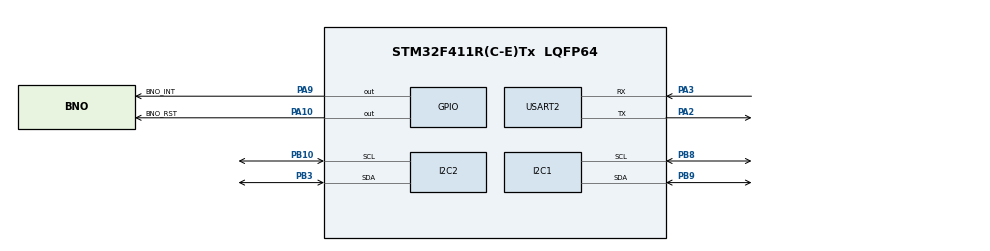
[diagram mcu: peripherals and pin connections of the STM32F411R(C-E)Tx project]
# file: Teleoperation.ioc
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I2C1.I2C_Mode=I2C_Fast
I2C2.I2C_Mode=I2C_Fast
Mcu.Family=STM32F4
Mcu.Name=STM32F411R(C-E)Tx
Mcu.Package=LQFP64
NVIC.PriorityGroup=NVIC_PRIORITYGROUP_4
PA10.GPIO_Label=BNO_RST
PA10.Signal=GPIO_Output
PA2.Mode=Asynchronous
PA2.Signal=USART2_TX
PA3.Mode=Asynchronous
PA3.Signal=USART2_RX
PA9.GPIO_Label=BNO_INT
PA9.Signal=GPIO_Output
PB10.Mode=I2C
PB10.Signal=I2C2_SCL
PB3.Mode=I2C
PB3.Signal=I2C2_SDA
PB8.Mode=I2C
PB8.Signal=I2C1_SCL
PB9.Mode=I2C
PB9.Signal=I2C1_SDA
ProjectManager.HeapSize=0x200
ProjectManager.StackSize=0x400
ProjectManager.TargetToolchain=STM32CubeIDE
RCC.AHBFreq_Value=16000000
RCC.APB1Freq_Value=16000000
RCC.APB2Freq_Value=16000000
RCC.CortexFreq_Value=16000000
RCC.HSE_VALUE=25000000
RCC.HSI_VALUE=16000000
RCC.LSE_VALUE=32768
RCC.SYSCLKFreq_VALUE=16000000
RCC.VCOOutputFreq_Value=192000000
USART2.VirtualMode=VM_ASYNC
VP_TIM2_VS_ClockSourceINT.Mode=Internal
board=custom

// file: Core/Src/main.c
/* USER CODE BEGIN Header */
/**
  ******************************************************************************
  * @file           : main.c
  * @brief          : Main program body
  ******************************************************************************
  * @attention
  *
  * Copyright (c) 2026 STMicroelectronics.
  * All rights reserved.
  *
  * This software is licensed under terms that can be found in the LICENSE file
  * in the root directory of this software component.
  * If no LICENSE file comes with this software, it is provided AS-IS.
  *
  ******************************************************************************
  */
/* USER CODE END Header */
#include "main.h"

/* USER CODE BEGIN Includes */
#include <stdio.h>
#include <stdint.h>
#include <string.h>
#include "BNO_08x_I2C.h"
/* USER CODE END Includes */

/* USER CODE BEGIN PD */
#define LSM_MAG_ADDR  (0x1E << 1)
/* USER CODE END PD */

I2C_HandleTypeDef hi2c1;
I2C_HandleTypeDef hi2c2;

TIM_HandleTypeDef htim2;

UART_HandleTypeDef huart2;

/* USER CODE BEGIN PV */
volatile uint8_t BNO_Ready = 0;
/* USER CODE END PV */

void SystemClock_Config(void);
static void MX_GPIO_Init(void);
static void MX_I2C1_Init(void);
static void MX_TIM2_Init(void);
static void MX_USART2_UART_Init(void);
static void MX_I2C2_Init(void);

/* USER CODE BEGIN 0 */
int16_t bx = 0, by = 0, bz = 0;   // фон
uint8_t mag_calibrated = 0;

int mag_read_raw(int16_t *mx, int16_t *my, int16_t *mz)
{
    uint8_t buf[6];
    uint8_t status;

    if (HAL_I2C_Mem_Read(&hi2c2, LSM_MAG_ADDR, 0x09, I2C_MEMADD_SIZE_8BIT, &status, 1, 100) != HAL_OK)
        return 0;

    if (!(status & 0x01))
        return 0;

    if (HAL_I2C_Mem_Read(&hi2c2, LSM_MAG_ADDR, 0x03, I2C_MEMADD_SIZE_8BIT, buf, 6, 100) != HAL_OK)
        return 0;

    *mx = (int16_t)((buf[0] << 8) | buf[1]);
    *mz = (int16_t)((buf[2] << 8) | buf[3]);
    *my = (int16_t)((buf[4] << 8) | buf[5]);

    return 1;
}

/* USER CODE END 0 */

int main(void)
{

  /* MCU Configuration--------------------------------------------------------*/

  /* Reset of all peripherals, Initializes the Flash interface and the Systick. */
  HAL_Init();

  /* Configure the system clock */
  SystemClock_Config();

  /* Initialize all configured peripherals */
  MX_GPIO_Init();
  MX_I2C1_Init();
  MX_TIM2_Init();
  MX_USART2_UART_Init();
  MX_I2C2_Init();
  /* USER CODE BEGIN 2 */

  #define MAG_AVERAGE_1  0x00  // 00
  #define MAG_AVERAGE_2  0x01  // 01
  #define MAG_AVERAGE_4  0x02  // 10
  #define MAG_AVERAGE_8  0x03  // 11

  #define MAG_RATE_0_75  0x00  // 000
  #define MAG_RATE_1_5   0x01  // 001
  #define MAG_RATE_3     0x02  // 010
  #define MAG_RATE_7_5   0x03  // 011
  #define MAG_RATE_15    0x04  // 100
  #define MAG_RATE_30    0x05  // 101
  #define MAG_RATE_75    0x06  // 110
  #define MAG_RATE_200    0x07  // 110

  uint8_t averaging = MAG_AVERAGE_1;
  uint8_t rate = MAG_RATE_75;
  uint8_t mode = 0x00; // 0x00 - нормальный режим

  uint8_t d = (averaging << 5) | (rate << 2) | mode;

  // CRA_REG_M
  HAL_I2C_Mem_Write(&hi2c2, LSM_MAG_ADDR, 0x00, 1, &d, 1, 1000);

  d = 0xE0;
  HAL_I2C_Mem_Write(&hi2c2, LSM_MAG_ADDR, 0x01, 1, &d, 1, 1000);

	// MR_REG_M (0x02): continuous-conversion
  d = 0x00;
  HAL_I2C_Mem_Write(&hi2c2, LSM_MAG_ADDR, 0x02, 1, &d, 1, 1000);

  HAL_TIM_Base_Start(&htim2);
  printf("Start!\r\n");
  printf("INT pin state: %d\r\n",
      HAL_GPIO_ReadPin(BNO_INT_GPIO_Port, BNO_INT_Pin));
  HAL_Delay(100);

  // Вручную сбрасываем сенсор
  HAL_GPIO_WritePin(BNO_RST_GPIO_Port, BNO_RST_Pin, GPIO_PIN_RESET); // RST = 0
  HAL_Delay(100);
  HAL_GPIO_WritePin(BNO_RST_GPIO_Port, BNO_RST_Pin, GPIO_PIN_SET);   // RST = 1
  HAL_Delay(1000);
  printf("Сканирование I2C...\r\n");
  uint8_t found = 0;

  for (uint8_t addr = 1; addr < 128; addr++) {
      if (HAL_I2C_IsDeviceReady(&hi2c1, addr << 1, 2, 10) == HAL_OK) {
          printf("Найдено: 0x%02X\r\n", addr);
          found++;
      }
  }
  if (!found) printf("Устройств не найдено!\r\n");
  BNO_Ready = 1;
  HAL_Delay(500);
  if (BNO_Init() == HAL_OK) {
      printf("BNO сенсор найден!\r\n");
      BNO_setFeature(ROTATION_VECTOR,           13333, 0);
      HAL_Delay(100);
  } else {
      printf("ОШИБКА: сенсор не отвечает!\r\n");
      Error_Handler();
  }
  /* USER CODE END 2 */

  /* Infinite loop */
  /* USER CODE BEGIN WHILE */
  BNO_RotationVectorWAcc_t quat = {0};

  char msg[500];
  while (1)
  {
    /* USER CODE END WHILE */

    /* USER CODE BEGIN 3 */
	if (BNO_dataAvailable() == HAL_OK)
	{
		switch(sensorData.sensorId)
		{
			case ROTATION_VECTOR:
				quat = getRotationVector();  // или raw quaternion
				brSeak;
		}
	}

	int n = snprintf(msg, sizeof(msg),
			"%.3f,%.3f,%.3f,%.3f\r\n",
			quat.I, quat.J, quat.K, quat.Real);
	HAL_UART_Transmit(&huart2, (uint8_t*)msg, n, 1000);

	HAL_Delay(1);
  /* USER CODE END 3 */
}
}

void SystemClock_Config(void)
{
  RCC_OscInitTypeDef RCC_OscInitStruct = {0};
  RCC_ClkInitTypeDef RCC_ClkInitStruct = {0};

  /** Configure the main internal regulator output voltage
  */
  __HAL_RCC_PWR_CLK_ENABLE();
  __HAL_PWR_VOLTAGESCALING_CONFIG(PWR_REGULATOR_VOLTAGE_SCALE1);

  /** Initializes the RCC Oscillators according to the specified parameters
  * in the RCC_OscInitTypeDef structure.
  */
  RCC_OscInitStruct.OscillatorType = RCC_OSCILLATORTYPE_HSI;
  RCC_OscInitStruct.HSIState = RCC_HSI_ON;
  RCC_OscInitStruct.HSICalibrationValue = RCC_HSICALIBRATION_DEFAULT;
  RCC_OscInitStruct.PLL.PLLState = RCC_PLL_ON;
  RCC_OscInitStruct.PLL.PLLSource = RCC_PLLSOURCE_HSI;
  RCC_OscInitStruct.PLL.PLLM = 8;
  RCC_OscInitStruct.PLL.PLLN = 100;
  RCC_OscInitStruct.PLL.PLLP = RCC_PLLP_DIV2;
  RCC_OscInitStruct.PLL.PLLQ = 4;
  if (HAL_RCC_OscConfig(&RCC_OscInitStruct) != HAL_OK)
  {
    Error_Handler();
  }

  /** Initializes the CPU, AHB and APB buses clocks
  */
  RCC_ClkInitStruct.ClockType = RCC_CLOCKTYPE_HCLK|RCC_CLOCKTYPE_SYSCLK
                              |RCC_CLOCKTYPE_PCLK1|RCC_CLOCKTYPE_PCLK2;
  RCC_ClkInitStruct.SYSCLKSource = RCC_SYSCLKSOURCE_PLLCLK;
  RCC_ClkInitStruct.AHBCLKDivider = RCC_SYSCLK_DIV1;
  RCC_ClkInitStruct.APB1CLKDivider = RCC_HCLK_DIV2;
  RCC_ClkInitStruct.APB2CLKDivider = RCC_HCLK_DIV1;

  if (HAL_RCC_ClockConfig(&RCC_ClkInitStruct, FLASH_LATENCY_3) != HAL_OK)
  {
    Error_Handler();
  }
}

static void MX_I2C1_Init(void)
{

  hi2c1.Instance = I2C1;
  hi2c1.Init.ClockSpeed = 100000;
  hi2c1.Init.DutyCycle = I2C_DUTYCYCLE_2;
  hi2c1.Init.OwnAddress1 = 0;
  hi2c1.Init.AddressingMode = I2C_ADDRESSINGMODE_7BIT;
  hi2c1.Init.DualAddressMode = I2C_DUALADDRESS_DISABLE;
  hi2c1.Init.OwnAddress2 = 0;
  hi2c1.Init.GeneralCallMode = I2C_GENERALCALL_DISABLE;
  hi2c1.Init.NoStretchMode = I2C_NOSTRETCH_DISABLE;
  if (HAL_I2C_Init(&hi2c1) != HAL_OK)
  {
    Error_Handler();
  }

}

static void MX_I2C2_Init(void)
{

  hi2c2.Instance = I2C2;
  hi2c2.Init.ClockSpeed = 100000;
  hi2c2.Init.DutyCycle = I2C_DUTYCYCLE_2;
  hi2c2.Init.OwnAddress1 = 0;
  hi2c2.Init.AddressingMode = I2C_ADDRESSINGMODE_7BIT;
  hi2c2.Init.DualAddressMode = I2C_DUALADDRESS_DISABLE;
  hi2c2.Init.OwnAddress2 = 0;
  hi2c2.Init.GeneralCallMode = I2C_GENERALCALL_DISABLE;
  hi2c2.Init.NoStretchMode = I2C_NOSTRETCH_DISABLE;
  if (HAL_I2C_Init(&hi2c2) != HAL_OK)
  {
    Error_Handler();
  }

}

static void MX_TIM2_Init(void)
{

  TIM_ClockConfigTypeDef sClockSourceConfig = {0};
  TIM_MasterConfigTypeDef sMasterConfig = {0};

  htim2.Instance = TIM2;
  htim2.Init.Prescaler = 0;
  htim2.Init.CounterMode = TIM_COUNTERMODE_UP;
  htim2.Init.Period = 4294967295;
  htim2.Init.ClockDivision = TIM_CLOCKDIVISION_DIV1;
  htim2.Init.AutoReloadPreload = TIM_AUTORELOAD_PRELOAD_DISABLE;
  if (HAL_TIM_Base_Init(&htim2) != HAL_OK)
  {
    Error_Handler();
  }
  sClockSourceConfig.ClockSource = TIM_CLOCKSOURCE_INTERNAL;
  if (HAL_TIM_ConfigClockSource(&htim2, &sClockSourceConfig) != HAL_OK)
  {
    Error_Handler();
  }
  sMasterConfig.MasterOutputTrigger = TIM_TRGO_RESET;
  sMasterConfig.MasterSlaveMode = TIM_MASTERSLAVEMODE_DISABLE;
  if (HAL_TIMEx_MasterConfigSynchronization(&htim2, &sMasterConfig) != HAL_OK)
  {
    Error_Handler();
  }

}

static void MX_USART2_UART_Init(void)
{

  huart2.Instance = USART2;
  huart2.Init.BaudRate = 921600;
  huart2.Init.WordLength = UART_WORDLENGTH_8B;
  huart2.Init.StopBits = UART_STOPBITS_1;
  huart2.Init.Parity = UART_PARITY_NONE;
  huart2.Init.Mode = UART_MODE_TX_RX;
  huart2.Init.HwFlowCtl = UART_HWCONTROL_NONE;
  huart2.Init.OverSampling = UART_OVERSAMPLING_16;
  if (HAL_UART_Init(&huart2) != HAL_OK)
  {
    Error_Handler();
  }

}

static void MX_GPIO_Init(void)
{
  GPIO_InitTypeDef GPIO_InitStruct = {0};

  /* GPIO Ports Clock Enable */
  __HAL_RCC_GPIOA_CLK_ENABLE();
  __HAL_RCC_GPIOB_CLK_ENABLE();
  __HAL_RCC_GPIOC_CLK_ENABLE();

  /*Configure GPIO pin Output Level */
  HAL_GPIO_WritePin(BNO_RST_GPIO_Port, BNO_RST_Pin, GPIO_PIN_SET);

  /*Configure GPIO pin : PC9 */
  GPIO_InitStruct.Pin = GPIO_PIN_9;
  GPIO_InitStruct.Mode = GPIO_MODE_AF_OD;
  GPIO_InitStruct.Pull = GPIO_NOPULL;
  GPIO_InitStruct.Speed = GPIO_SPEED_FREQ_VERY_HIGH;
  GPIO_InitStruct.Alternate = GPIO_AF4_I2C3;
  HAL_GPIO_Init(GPIOC, &GPIO_InitStruct);

  /*Configure GPIO pin : PA8 */
  GPIO_InitStruct.Pin = GPIO_PIN_8;
  GPIO_InitStruct.Mode = GPIO_MODE_AF_OD;
  GPIO_InitStruct.Pull = GPIO_NOPULL;
  GPIO_InitStruct.Speed = GPIO_SPEED_FREQ_VERY_HIGH;
  GPIO_InitStruct.Alternate = GPIO_AF4_I2C3;
  HAL_GPIO_Init(GPIOA, &GPIO_InitStruct);

  /*Configure GPIO pin : BNO_INT_Pin */
  GPIO_InitStruct.Pin = BNO_INT_Pin;
  GPIO_InitStruct.Mode = GPIO_MODE_IT_FALLING;
  GPIO_InitStruct.Pull = GPIO_PULLUP;
  HAL_GPIO_Init(BNO_INT_GPIO_Port, &GPIO_InitStruct);

  /*Configure GPIO pin : BNO_RST_Pin */
  GPIO_InitStruct.Pin = BNO_RST_Pin;
  GPIO_InitStruct.Mode = GPIO_MODE_OUTPUT_PP;
  GPIO_InitStruct.Pull = GPIO_NOPULL;
  GPIO_InitStruct.Speed = GPIO_SPEED_FREQ_LOW;
  HAL_GPIO_Init(BNO_RST_GPIO_Port, &GPIO_InitStruct);

  /* EXTI interrupt init*/
  HAL_NVIC_SetPriority(EXTI9_5_IRQn, 0, 0);
  HAL_NVIC_EnableIRQ(EXTI9_5_IRQn);

}

/* USER CODE BEGIN 4 */
int __io_putchar(int ch) {
    HAL_UART_Transmit(&huart2, (uint8_t *)&ch, 1, HAL_MAX_DELAY);
    return ch;
}

void HAL_GPIO_EXTI_Callback(uint16_t GPIO_Pin) {
    if (GPIO_Pin == BNO_INT_Pin) {
        BNO_Ready = 1;
    }
}
/* USER CODE END 4 */

void Error_Handler(void)
{
  __disable_irq();
  while (1)
  {
  }
}
